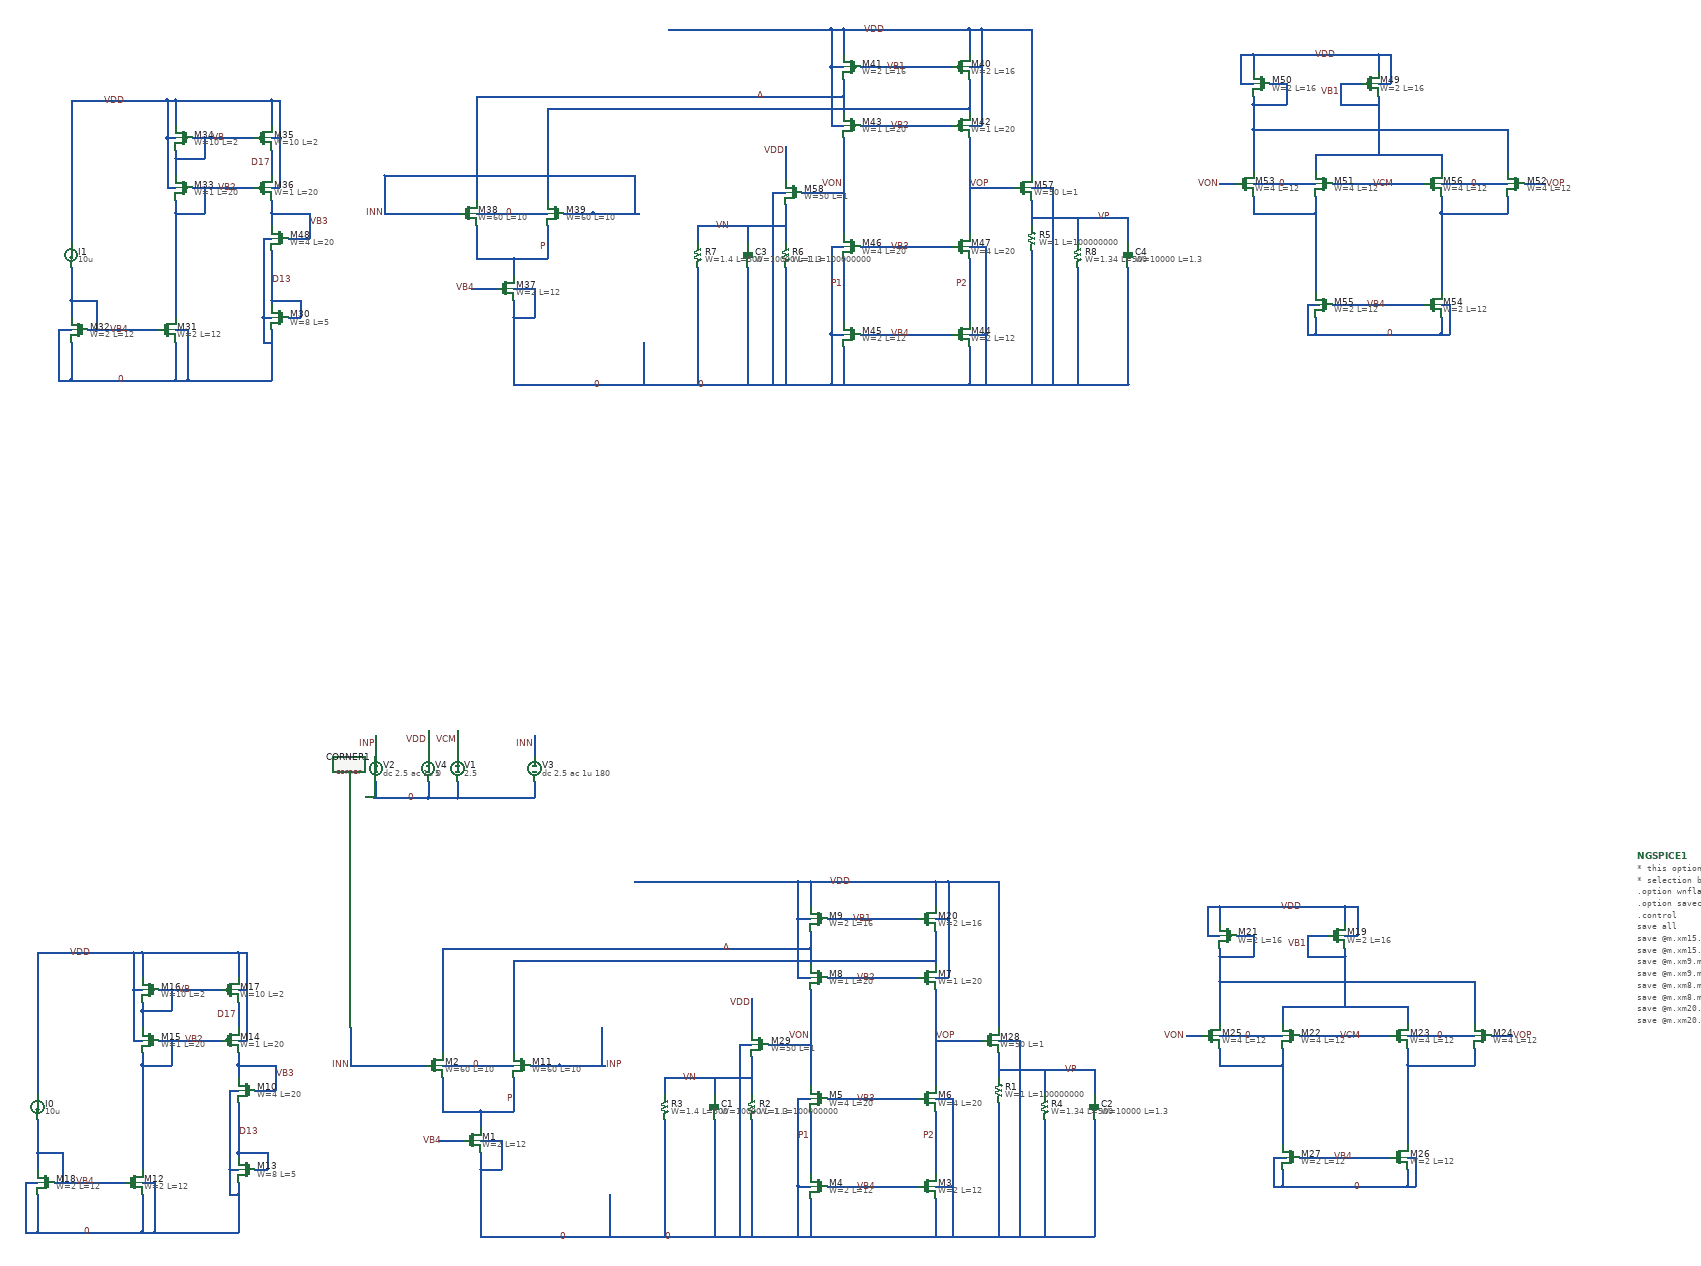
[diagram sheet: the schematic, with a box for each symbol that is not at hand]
v {xschem version=3.4.5 file_version=1.2
}
G {}
K {}
V {}
S {}
E {}
B 2 -210 300 1560 1150 {flags=graph
y1=-17.303233

ypos1=0
ypos2=2


unity=1


divx=5
subdivx=8
xlabmag=1.0
ylabmag=1.0


dataset=-1
unitx=1
logx=1
logy=0
color=4
node="\\"vp db20()\\""
x1=2.4468025
hilight_wave=-1

y2=-15.322405

divy=10
subdivy=4
x2=6.935988}
B 2 -1120 400 -320 800 {flags=graph
y1=26.38169

ypos1=0
ypos2=2
divy=5
subdivy=1
unity=1
x1=2.4468025

divx=5
subdivx=1
xlabmag=1.0
ylabmag=1.0
node=ph(vp)
color=4
dataset=-1
unitx=1
logx=0
logy=0

y2=80.30864
x2=6.935988}
N -130 -610 -130 -550 {
lab=VDD}
N 170 -610 170 -550 {
lab=VDD}
N 170 -420 170 -410 {
lab=#net1}
N -130 -450 -130 -410 {
lab=A}
N -130 -350 -130 -120 {
lab=VON}
N -130 -60 -130 90 {
lab=P1}
N -130 150 -130 240 {
lab=0}
N -130 240 170 240 {
lab=0}
N 170 150 170 240 {
lab=0}
N 170 -60 170 90 {
lab=P2}
N 170 -350 170 -120 {
lab=VOP}
N -90 -90 130 -90 {
lab=VB3}
N -90 120 130 120 {
lab=VB4}
N -160 120 -130 120 {
lab=0}
N -160 120 -160 240 {
lab=0}
N -160 240 -130 240 {
lab=0}
N 170 120 210 120 {
lab=0}
N 210 120 210 240 {
lab=0}
N 170 240 210 240 {
lab=0}
N -160 -90 -130 -90 {
lab=0}
N -160 -90 -160 120 {
lab=0}
N 170 -90 210 -90 {
lab=0}
N 210 -90 210 120 {
lab=0}
N -1010 -170 -840 -170 {
lab=0}
N -1100 -170 -1050 -170 {
lab=INN}
N -800 -170 -760 -170 {
lab=INP}
N -1010 -140 -1010 -60 {
lab=P}
N -920 -60 -840 -60 {
lab=P}
N -840 -140 -840 -60 {
lab=P}
N -920 -60 -920 -20 {
lab=P}
N -1020 10 -960 10 {
lab=VB4}
N -920 80 -920 240 {
lab=0}
N -540 240 -160 240 {
lab=0}
N -90 -380 130 -380 {
lab=VB2}
N -90 -520 130 -520 {
lab=VB1}
N 170 -520 200 -520 {
lab=VDD}
N 200 -610 200 -520 {
lab=VDD}
N 170 -610 200 -610 {
lab=VDD}
N -160 -520 -130 -520 {
lab=VDD}
N -160 -610 -160 -520 {
lab=VDD}
N -130 -610 170 -610 {
lab=VDD}
N 170 -380 200 -380 {
lab=VDD}
N 200 -520 200 -380 {
lab=VDD}
N -160 -380 -130 -380 {
lab=VDD}
N -160 -520 -160 -380 {
lab=VDD}
N -1010 -450 -1010 -200 {
lab=A}
N -630 -450 -130 -450 {
lab=A}
N -840 -420 -840 -200 {
lab=#net1}
N -460 -420 170 -420 {
lab=#net1}
N -1980 40 -1980 80 {
lab=VB4}
N -1980 140 -1980 230 {
lab=0}
N -1730 140 -1730 230 {
lab=0}
N -1730 110 -1700 110 {
lab=0}
N -1700 110 -1700 230 {
lab=0}
N -1730 230 -1700 230 {
lab=0}
N -2010 110 -1980 110 {
lab=0}
N -2010 110 -2010 230 {
lab=0}
N -2010 230 -1980 230 {
lab=0}
N -1920 110 -1770 110 {
lab=VB4}
N -1980 40 -1920 40 {
lab=VB4}
N -1920 40 -1920 110 {
lab=VB4}
N -1730 -440 -1730 -380 {
lab=VDD}
N -1730 -440 -1500 -440 {
lab=VDD}
N -1500 -440 -1500 -380 {
lab=VDD}
N -1660 -350 -1540 -350 {
lab=VB}
N -1660 -350 -1660 -300 {
lab=VB}
N -1730 -300 -1660 -300 {
lab=VB}
N -1730 -300 -1730 -260 {
lab=VB}
N -1980 -440 -1980 -100 {
lab=VDD}
N -1750 -440 -1730 -440 {
lab=VDD}
N -1730 -170 -1730 80 {
lab=VB2}
N -1660 -230 -1540 -230 {
lab=VB2}
N -1660 -230 -1660 -170 {
lab=VB2}
N -1730 -170 -1660 -170 {
lab=VB2}
N -1500 -320 -1500 -260 {
lab=D17}
N -1500 -230 -1480 -230 {
lab=VDD}
N -1480 -350 -1480 -230 {
lab=VDD}
N -1500 -440 -1480 -440 {
lab=VDD}
N -1500 -350 -1480 -350 {
lab=VDD}
N -1750 -230 -1730 -230 {
lab=VDD}
N -1750 -350 -1750 -230 {
lab=VDD}
N -1750 -350 -1730 -350 {
lab=VDD}
N -1500 -170 -1500 -140 {
lab=VB3}
N -1500 40 -1500 50 {
lab=D13}
N -1460 -110 -1410 -110 {
lab=VB3}
N -1410 -170 -1410 -110 {
lab=VB3}
N -1500 -170 -1410 -170 {
lab=VB3}
N -1500 140 -1500 230 {
lab=0}
N -1700 230 -1500 230 {
lab=0}
N -1520 80 -1500 80 {
lab=0}
N -1520 80 -1520 140 {
lab=0}
N -1520 140 -1500 140 {
lab=0}
N -1460 80 -1430 80 {
lab=D13}
N -1430 40 -1430 80 {
lab=D13}
N -1500 40 -1430 40 {
lab=D13}
N -1045 -970 -1045 -910 {
lab=VDD}
N -1175 -810 -1045 -810 {
lab=0}
N -1045 -850 -1045 -810 {
lab=0}
N -920 10 -870 10 {
lab=0}
N -870 10 -870 80 {
lab=0}
N -920 80 -870 80 {
lab=0}
N -1520 -110 -1520 80 {
lab=0}
N -1520 -110 -1500 -110 {
lab=0}
N 1150 -480 1180 -480 {
lab=VDD}
N 820 -480 850 -480 {
lab=VDD}
N 1040 -240 1260 -240 {
lab=VCM}
N 1300 -240 1460 -240 {
lab=0}
N 980 50 1010 50 {
lab=0}
N 1300 50 1320 50 {
lab=0}
N 1000 -310 1000 -270 {
lab=VB1}
N 1150 -310 1300 -310 {
lab=VB1}
N 1300 -310 1300 -270 {
lab=VB1}
N 850 -370 850 -270 {
lab=#net2}
N 850 -370 1460 -370 {
lab=#net2}
N 1460 -370 1460 -270 {
lab=#net2}
N 850 -430 850 -370 {
lab=#net2}
N 1150 -430 1150 -310 {
lab=VB1}
N 850 -210 850 -170 {
lab=#net3}
N 850 -170 1000 -170 {
lab=#net3}
N 1000 -210 1000 -170 {
lab=#net3}
N 1300 -210 1300 -170 {
lab=#net4}
N 1300 -170 1460 -170 {
lab=#net4}
N 1460 -210 1460 -170 {
lab=#net4}
N 1000 -170 1000 20 {
lab=#net3}
N 1300 -170 1300 20 {
lab=#net4}
N 1040 50 1270 50 {
lab=VB4}
N 1000 80 1000 120 {
lab=0}
N 1000 120 1300 120 {
lab=0}
N 1300 80 1300 120 {
lab=0}
N 930 -480 930 -430 {
lab=#net2}
N 850 -430 930 -430 {
lab=#net2}
N 1060 -480 1060 -430 {
lab=VB1}
N 1060 -430 1150 -430 {
lab=VB1}
N 890 -480 930 -480 {
lab=#net2}
N 1060 -480 1110 -480 {
lab=VB1}
N 850 -550 850 -510 {
lab=VDD}
N 1150 -550 1150 -510 {
lab=VDD}
N 770 -240 810 -240 {
lab=VON}
N 1500 -240 1550 -240 {
lab=VOP}
N 820 -550 820 -480 {
lab=VDD}
N 850 -550 1150 -550 {
lab=VDD}
N 1180 -550 1180 -480 {
lab=VDD}
N 1150 -550 1180 -550 {
lab=VDD}
N 980 50 980 120 {
lab=0}
N 980 120 1000 120 {
lab=0}
N 1320 50 1320 120 {
lab=0}
N 1300 120 1320 120 {
lab=0}
N -975 -970 -975 -910 {
lab=VCM}
N -975 -850 -975 -810 {
lab=0}
N -975 -810 -790 -810 {
lab=0}
N -790 -960 -790 -910 {
lab=INN}
N -790 -850 -790 -810 {
lab=0}
N -160 -610 -130 -610 {
lab=VDD}
N -1010 -60 -920 -60 {
lab=P}
N -130 -490 -130 -450 {
lab=A}
N 170 -490 170 -420 {
lab=#net1}
N -1980 -40 -1980 40 {
lab=VB4}
N -1940 110 -1920 110 {
lab=VB4}
N -1690 -350 -1660 -350 {
lab=VB}
N -1730 -320 -1730 -300 {
lab=VB}
N -1690 -230 -1660 -230 {
lab=VB2}
N -1730 -200 -1730 -170 {
lab=VB2}
N -1480 -440 -1480 -350 {
lab=VDD}
N -1980 -440 -1750 -440 {
lab=VDD}
N -1750 -440 -1750 -350 {
lab=VDD}
N -1500 -200 -1500 -170 {
lab=VB3}
N -1500 110 -1500 140 {
lab=0}
N -1500 -80 -1500 40 {
lab=D13}
N -920 40 -920 80 {
lab=0}
N 850 -240 1000 -240 {
lab=0}
N 1000 -310 1150 -310 {
lab=VB1}
N 850 -450 850 -430 {
lab=#net2}
N 1150 -450 1150 -430 {
lab=VB1}
N 820 -550 850 -550 {
lab=VDD}
N -1045 -810 -975 -810 {
lab=0}
N -1980 230 -1730 230 {
lab=0}
N 170 -230 280 -230 {
lab=VOP}
N 200 -610 310 -610 {
lab=VDD}
N 320 -230 350 -230 {
lab=0}
N 350 -230 370 -230 {
lab=0}
N 320 -610 320 -260 {
lab=VDD}
N 280 -610 320 -610 {
lab=VDD}
N 320 -200 320 -140 {
lab=VP}
N 320 -80 320 240 {
lab=0}
N 210 240 320 240 {
lab=0}
N -270 -330 -270 -250 {
lab=VDD}
N -230 -220 -130 -220 {
lab=VON}
N -270 -190 -270 -100 {
lab=VN}
N -270 -40 -270 240 {
lab=0}
N -300 -220 -270 -220 {
lab=0}
N -300 -220 -300 230 {
lab=0}
N -300 230 -300 240 {
lab=0}
N 370 -230 370 230 {
lab=0}
N 370 230 370 240 {
lab=0}
N 320 240 370 240 {
lab=0}
N -1010 -450 -910 -450 {
lab=A}
N -560 -420 -460 -420 {
lab=#net1}
N -920 240 -820 240 {
lab=0}
N -420 -140 -270 -140 {
lab=VN}
N -480 -140 -480 -100 {
lab=VN}
N -360 -140 -360 -100 {
lab=VN}
N -480 -40 -480 240 {
lab=0}
N -360 -40 -360 240 {
lab=0}
N -480 -140 -420 -140 {
lab=VN}
N 430 -140 430 -100 {
lab=VP}
N 550 -140 550 -100 {
lab=VP}
N 430 -40 430 240 {
lab=0}
N 550 -40 550 240 {
lab=0}
N 320 -160 550 -160 {
lab=VP}
N 550 -160 550 -140 {
lab=VP}
N 430 -160 430 -140 {
lab=VP}
N 380 240 550 240 {
lab=0}
N 330 240 550 240 {
lab=0}
N -550 -610 -160 -610 {
lab=VDD}
N -1120 -170 -1080 -170 {
lab=INN}
N -1230 -170 -1180 -170 {
lab=INN}
N -830 240 -520 240 {
lab=0}
N -920 -450 -590 -450 {
lab=A}
N -840 -420 -550 -420 {
lab=#net1}
N -770 -170 -730 -170 {
lab=INP}
N -790 240 -410 240 {
lab=0}
N -770 -170 -730 -170 {
lab=INP}
N -670 -170 -620 -170 {
lab=INP}
N -610 140 -610 240 {
lab=0}
N -730 -170 -660 -170 {
lab=INP}
N -1180 -170 -1100 -170 {
lab=INN}
N -1230 -260 -1230 -170 {
lab=INN}
N -630 -260 -630 -170 {
lab=INP}
N -1170 -960 -1170 -910 {
lab=INP}
N -1170 -850 -1170 -810 {
lab=0}
N -50 -2650 -50 -2590 {
lab=VDD}
N 250 -2650 250 -2590 {
lab=VDD}
N 250 -2460 250 -2450 {
lab=#net1}
N -50 -2490 -50 -2450 {
lab=A}
N -50 -2390 -50 -2160 {
lab=VON}
N -50 -2100 -50 -1950 {
lab=P1}
N -50 -1890 -50 -1800 {
lab=0}
N -50 -1800 250 -1800 {
lab=0}
N 250 -1890 250 -1800 {
lab=0}
N 250 -2100 250 -1950 {
lab=P2}
N 250 -2390 250 -2160 {
lab=VOP}
N -10 -2130 210 -2130 {
lab=VB3}
N -10 -1920 210 -1920 {
lab=VB4}
N -80 -1920 -50 -1920 {
lab=0}
N -80 -1920 -80 -1800 {
lab=0}
N -80 -1800 -50 -1800 {
lab=0}
N 250 -1920 290 -1920 {
lab=0}
N 290 -1920 290 -1800 {
lab=0}
N 250 -1800 290 -1800 {
lab=0}
N -80 -2130 -50 -2130 {
lab=0}
N -80 -2130 -80 -1920 {
lab=0}
N 250 -2130 290 -2130 {
lab=0}
N 290 -2130 290 -1920 {
lab=0}
N -930 -2210 -760 -2210 {
lab=0}
N -1020 -2210 -970 -2210 {
lab=INN}
N -720 -2210 -680 -2210 {
lab=INP}
N -930 -2180 -930 -2100 {
lab=P}
N -840 -2100 -760 -2100 {
lab=P}
N -760 -2180 -760 -2100 {
lab=P}
N -840 -2100 -840 -2060 {
lab=P}
N -940 -2030 -880 -2030 {
lab=VB4}
N -840 -1960 -840 -1800 {
lab=0}
N -460 -1800 -80 -1800 {
lab=0}
N -10 -2420 210 -2420 {
lab=VB2}
N -10 -2560 210 -2560 {
lab=VB1}
N 250 -2560 280 -2560 {
lab=VDD}
N 280 -2650 280 -2560 {
lab=VDD}
N 250 -2650 280 -2650 {
lab=VDD}
N -80 -2560 -50 -2560 {
lab=VDD}
N -80 -2650 -80 -2560 {
lab=VDD}
N -50 -2650 250 -2650 {
lab=VDD}
N 250 -2420 280 -2420 {
lab=VDD}
N 280 -2560 280 -2420 {
lab=VDD}
N -80 -2420 -50 -2420 {
lab=VDD}
N -80 -2560 -80 -2420 {
lab=VDD}
N -930 -2490 -930 -2240 {
lab=A}
N -550 -2490 -50 -2490 {
lab=A}
N -760 -2460 -760 -2240 {
lab=#net1}
N -380 -2460 250 -2460 {
lab=#net1}
N -1900 -2000 -1900 -1960 {
lab=VB4}
N -1900 -1900 -1900 -1810 {
lab=0}
N -1650 -1900 -1650 -1810 {
lab=0}
N -1650 -1930 -1620 -1930 {
lab=0}
N -1620 -1930 -1620 -1810 {
lab=0}
N -1650 -1810 -1620 -1810 {
lab=0}
N -1930 -1930 -1900 -1930 {
lab=0}
N -1930 -1930 -1930 -1810 {
lab=0}
N -1930 -1810 -1900 -1810 {
lab=0}
N -1840 -1930 -1690 -1930 {
lab=VB4}
N -1900 -2000 -1840 -2000 {
lab=VB4}
N -1840 -2000 -1840 -1930 {
lab=VB4}
N -1650 -2480 -1650 -2420 {
lab=VDD}
N -1650 -2480 -1420 -2480 {
lab=VDD}
N -1420 -2480 -1420 -2420 {
lab=VDD}
N -1580 -2390 -1460 -2390 {
lab=VB}
N -1580 -2390 -1580 -2340 {
lab=VB}
N -1650 -2340 -1580 -2340 {
lab=VB}
N -1650 -2340 -1650 -2300 {
lab=VB}
N -1900 -2480 -1900 -2140 {
lab=VDD}
N -1670 -2480 -1650 -2480 {
lab=VDD}
N -1650 -2210 -1650 -1960 {
lab=VB2}
N -1580 -2270 -1460 -2270 {
lab=VB2}
N -1580 -2270 -1580 -2210 {
lab=VB2}
N -1650 -2210 -1580 -2210 {
lab=VB2}
N -1420 -2360 -1420 -2300 {
lab=D17}
N -1420 -2270 -1400 -2270 {
lab=VDD}
N -1400 -2390 -1400 -2270 {
lab=VDD}
N -1420 -2480 -1400 -2480 {
lab=VDD}
N -1420 -2390 -1400 -2390 {
lab=VDD}
N -1670 -2270 -1650 -2270 {
lab=VDD}
N -1670 -2390 -1670 -2270 {
lab=VDD}
N -1670 -2390 -1650 -2390 {
lab=VDD}
N -1420 -2210 -1420 -2180 {
lab=VB3}
N -1420 -2000 -1420 -1990 {
lab=D13}
N -1380 -2150 -1330 -2150 {
lab=VB3}
N -1330 -2210 -1330 -2150 {
lab=VB3}
N -1420 -2210 -1330 -2210 {
lab=VB3}
N -1420 -1900 -1420 -1810 {
lab=0}
N -1620 -1810 -1420 -1810 {
lab=0}
N -1440 -1960 -1420 -1960 {
lab=0}
N -1440 -1960 -1440 -1900 {
lab=0}
N -1440 -1900 -1420 -1900 {
lab=0}
N -1380 -1960 -1350 -1960 {
lab=D13}
N -1350 -2000 -1350 -1960 {
lab=D13}
N -1420 -2000 -1350 -2000 {
lab=D13}
N -840 -2030 -790 -2030 {
lab=0}
N -790 -2030 -790 -1960 {
lab=0}
N -840 -1960 -790 -1960 {
lab=0}
N -1440 -2150 -1440 -1960 {
lab=0}
N -1440 -2150 -1420 -2150 {
lab=0}
N 1230 -2520 1260 -2520 {
lab=VDD}
N 900 -2520 930 -2520 {
lab=VDD}
N 1120 -2280 1340 -2280 {
lab=VCM}
N 1380 -2280 1540 -2280 {
lab=0}
N 1060 -1990 1090 -1990 {
lab=0}
N 1380 -1990 1400 -1990 {
lab=0}
N 1080 -2350 1080 -2310 {
lab=VB1}
N 1230 -2350 1380 -2350 {
lab=VB1}
N 1380 -2350 1380 -2310 {
lab=VB1}
N 930 -2410 930 -2310 {
lab=#net2}
N 930 -2410 1540 -2410 {
lab=#net2}
N 1540 -2410 1540 -2310 {
lab=#net2}
N 930 -2470 930 -2410 {
lab=#net2}
N 1230 -2470 1230 -2350 {
lab=VB1}
N 930 -2250 930 -2210 {
lab=#net3}
N 930 -2210 1080 -2210 {
lab=#net3}
N 1080 -2250 1080 -2210 {
lab=#net3}
N 1380 -2250 1380 -2210 {
lab=#net4}
N 1380 -2210 1540 -2210 {
lab=#net4}
N 1540 -2250 1540 -2210 {
lab=#net4}
N 1080 -2210 1080 -2020 {
lab=#net3}
N 1380 -2210 1380 -2020 {
lab=#net4}
N 1120 -1990 1350 -1990 {
lab=VB4}
N 1080 -1960 1080 -1920 {
lab=0}
N 1080 -1920 1380 -1920 {
lab=0}
N 1380 -1960 1380 -1920 {
lab=0}
N 1010 -2520 1010 -2470 {
lab=#net2}
N 930 -2470 1010 -2470 {
lab=#net2}
N 1140 -2520 1140 -2470 {
lab=VB1}
N 1140 -2470 1230 -2470 {
lab=VB1}
N 970 -2520 1010 -2520 {
lab=#net2}
N 1140 -2520 1190 -2520 {
lab=VB1}
N 930 -2590 930 -2550 {
lab=VDD}
N 1230 -2590 1230 -2550 {
lab=VDD}
N 850 -2280 890 -2280 {
lab=VON}
N 1580 -2280 1630 -2280 {
lab=VOP}
N 900 -2590 900 -2520 {
lab=VDD}
N 930 -2590 1230 -2590 {
lab=VDD}
N 1260 -2590 1260 -2520 {
lab=VDD}
N 1230 -2590 1260 -2590 {
lab=VDD}
N 1060 -1990 1060 -1920 {
lab=0}
N 1060 -1920 1080 -1920 {
lab=0}
N 1400 -1990 1400 -1920 {
lab=0}
N 1380 -1920 1400 -1920 {
lab=0}
N -80 -2650 -50 -2650 {
lab=VDD}
N -930 -2100 -840 -2100 {
lab=P}
N -50 -2530 -50 -2490 {
lab=A}
N 250 -2530 250 -2460 {
lab=#net1}
N -1900 -2080 -1900 -2000 {
lab=VB4}
N -1860 -1930 -1840 -1930 {
lab=VB4}
N -1610 -2390 -1580 -2390 {
lab=VB}
N -1650 -2360 -1650 -2340 {
lab=VB}
N -1610 -2270 -1580 -2270 {
lab=VB2}
N -1650 -2240 -1650 -2210 {
lab=VB2}
N -1400 -2480 -1400 -2390 {
lab=VDD}
N -1900 -2480 -1670 -2480 {
lab=VDD}
N -1670 -2480 -1670 -2390 {
lab=VDD}
N -1420 -2240 -1420 -2210 {
lab=VB3}
N -1420 -1930 -1420 -1900 {
lab=0}
N -1420 -2120 -1420 -2000 {
lab=D13}
N -840 -2000 -840 -1960 {
lab=0}
N 930 -2280 1080 -2280 {
lab=0}
N 1080 -2350 1230 -2350 {
lab=VB1}
N 930 -2490 930 -2470 {
lab=#net2}
N 1230 -2490 1230 -2470 {
lab=VB1}
N 900 -2590 930 -2590 {
lab=VDD}
N -1900 -1810 -1650 -1810 {
lab=0}
N 250 -2270 360 -2270 {
lab=VOP}
N 280 -2650 390 -2650 {
lab=VDD}
N 400 -2270 430 -2270 {
lab=0}
N 430 -2270 450 -2270 {
lab=0}
N 400 -2650 400 -2300 {
lab=VDD}
N 360 -2650 400 -2650 {
lab=VDD}
N 400 -2240 400 -2180 {
lab=VP}
N 400 -2120 400 -1800 {
lab=0}
N 290 -1800 400 -1800 {
lab=0}
N -190 -2370 -190 -2290 {
lab=VDD}
N -150 -2260 -50 -2260 {
lab=VON}
N -190 -2230 -190 -2140 {
lab=VN}
N -190 -2080 -190 -1800 {
lab=0}
N -220 -2260 -190 -2260 {
lab=0}
N -220 -2260 -220 -1810 {
lab=0}
N -220 -1810 -220 -1800 {
lab=0}
N 450 -2270 450 -1810 {
lab=0}
N 450 -1810 450 -1800 {
lab=0}
N 400 -1800 450 -1800 {
lab=0}
N -930 -2490 -830 -2490 {
lab=A}
N -480 -2460 -380 -2460 {
lab=#net1}
N -840 -1800 -740 -1800 {
lab=0}
N -340 -2180 -190 -2180 {
lab=VN}
N -400 -2180 -400 -2140 {
lab=VN}
N -280 -2180 -280 -2140 {
lab=VN}
N -400 -2080 -400 -1800 {
lab=0}
N -280 -2080 -280 -1800 {
lab=0}
N -400 -2180 -340 -2180 {
lab=VN}
N 510 -2180 510 -2140 {
lab=VP}
N 630 -2180 630 -2140 {
lab=VP}
N 510 -2080 510 -1800 {
lab=0}
N 630 -2080 630 -1800 {
lab=0}
N 400 -2200 630 -2200 {
lab=VP}
N 630 -2200 630 -2180 {
lab=VP}
N 510 -2200 510 -2180 {
lab=VP}
N 460 -1800 630 -1800 {
lab=0}
N 410 -1800 630 -1800 {
lab=0}
N -470 -2650 -80 -2650 {
lab=VDD}
N -1040 -2210 -1000 -2210 {
lab=INN}
N -1150 -2210 -1100 -2210 {
lab=INN}
N -750 -1800 -440 -1800 {
lab=0}
N -840 -2490 -510 -2490 {
lab=A}
N -760 -2460 -470 -2460 {
lab=#net1}
N -690 -2210 -650 -2210 {
lab=INP}
N -710 -1800 -330 -1800 {
lab=0}
N -690 -2210 -650 -2210 {
lab=INP}
N -590 -2210 -540 -2210 {
lab=INP}
N -530 -1900 -530 -1800 {
lab=0}
N -650 -2210 -580 -2210 {
lab=INP}
N -1100 -2210 -1020 -2210 {
lab=INN}
N -1150 -2300 -1150 -2210 {
lab=INN}
N -550 -2300 -550 -2210 {
lab=INP}
N -1150 -2300 -1140 -2300 {}
N -1150 -2300 -550 -2300 {}
C {devices/isource.sym} -1980 -70 0 0 {name=I0 value=10u
}
C {devices/lab_pin.sym} -1840 110 0 0 {name=p1 sig_type=std_logic lab=VB4
}
C {devices/lab_pin.sym} -1010 10 0 0 {name=p2 sig_type=std_logic lab=VB4}
C {devices/lab_pin.sym} 30 120 0 0 {name=p3 sig_type=std_logic lab=VB4}
C {devices/lab_pin.sym} -920 -170 0 0 {name=p4 sig_type=std_logic lab=0}
C {devices/lab_pin.sym} -460 240 1 0 {name=p7 sig_type=std_logic lab=0}
C {devices/lab_pin.sym} -1850 230 1 0 {name=p8 sig_type=std_logic lab=0}
C {devices/lab_pin.sym} -1850 -440 1 0 {name=p9 sig_type=std_logic lab=VDD}
C {devices/lab_pin.sym} -30 -610 1 0 {name=p10 sig_type=std_logic lab=VDD}
C {devices/lab_pin.sym} 20 -520 1 0 {name=p13 sig_type=std_logic lab=VB1}
C {devices/lab_pin.sym} -1580 -230 1 0 {name=p14 sig_type=std_logic lab=VB2}
C {devices/lab_pin.sym} 30 -380 3 0 {name=p15 sig_type=std_logic lab=VB2}
C {devices/lab_pin.sym} -1410 -150 2 0 {name=p16 sig_type=std_logic lab=VB3}
C {devices/lab_pin.sym} 30 -90 1 0 {name=p17 sig_type=std_logic lab=VB3}
C {devices/code_shown.sym} 1850 -670 0 0 {name=NGSPICE1
only_toplevel=true
value="* this option enables mos model bin 
* selection based on W/NF instead of W
.option wnflag=1 
.option savecurrents

.control
save all
save @m.xm15.msky130_fd_pr__pfet_g5v0d10v5[vth]
save @m.xm15.msky130_fd_pr__pfet_g5v0d10v5[gm]
save @m.xm9.msky130_fd_pr__pfet_g5v0d10v5[vth]
save @m.xm9.msky130_fd_pr__pfet_g5v0d10v5[gm]
save @m.xm8.msky130_fd_pr__pfet_g5v0d10v5[vth]
save @m.xm8.msky130_fd_pr__pfet_g5v0d10v5[gm]
save @m.xm20.msky130_fd_pr__pfet_g5v0d10v5[vth]
save @m.xm20.msky130_fd_pr__pfet_g5v0d10v5[gm]
save @m.xm7.msky130_fd_pr__pfet_g5v0d10v5[vth]
save @m.xm7.msky130_fd_pr__pfet_g5v0d10v5[gm]
save @m.xm10.msky130_fd_pr__nfet_g5v0d10v5[gm]
save @m.xm10.msky130_fd_pr__nfet_g5v0d10v5[vth]
save @m.xm14.msky130_fd_pr__pfet_g5v0d10v5[gm]
save @m.xm14.msky130_fd_pr__pfet_g5v0d10v5[vth]
save @m.xm16.msky130_fd_pr__pfet_g5v0d10v5[gm]
save @m.xm16.msky130_fd_pr__pfet_g5v0d10v5[vth]
save @m.xm17.msky130_fd_pr__pfet_g5v0d10v5[gm]
save @m.xm17.msky130_fd_pr__pfet_g5v0d10v5[vth]
save @m.xm13.msky130_fd_pr__nfet_g5v0d10v5[gm]
save @m.xm13.msky130_fd_pr__nfet_g5v0d10v5[vth]
save @m.xm12.msky130_fd_pr__nfet_g5v0d10v5[vth]
save @m.xm18.msky130_fd_pr__nfet_g5v0d10v5[vth]
*folded 
save @m.xm2.msky130_fd_pr__nfet_g5v0d10v5[vth]
save @m.xm11.msky130_fd_pr__nfet_g5v0d10v5[vth]
save @m.xm1.msky130_fd_pr__nfet_g5v0d10v5[vth]
save @m.xm5.msky130_fd_pr__nfet_g5v0d10v5[vth]
save @m.xm6.msky130_fd_pr__nfet_g5v0d10v5[vth]
save @m.xm4.msky130_fd_pr__nfet_g5v0d10v5[vth]
save @m.xm3.msky130_fd_pr__nfet_g5v0d10v5[vth]
save @m.xm7.msky130_fd_pr__pfet_g5v0d10v5[vth]
save @m.xm8.msky130_fd_pr__pfet_g5v0d10v5[vth]
save @m.xm9.msky130_fd_pr__pfet_g5v0d10v5[vth]
save @m.xm20.msky130_fd_pr__pfet_g5v0d10v5[vth]
*CMFB
save @m.xm21.msky130_fd_pr__pfet_g5v0d10v5[vth]
save @m.xm19.msky130_fd_pr__pfet_g5v0d10v5[vth]
save @m.xm22.msky130_fd_pr__nfet_g5v0d10v5[vth]
save @m.xm23.msky130_fd_pr__nfet_g5v0d10v5[vth]
save @m.xm25.msky130_fd_pr__nfet_g5v0d10v5[vth]
save @m.xm27.msky130_fd_pr__nfet_g5v0d10v5[vth]
save @m.xm26.msky130_fd_pr__nfet_g5v0d10v5[vth]
save @m.xm24.msky130_fd_pr__nfet_g5v0d10v5[vth]
save current 


write CMRR_Folded.raw

op
print VON VOP VB2 VB
*print @m.xm18.msky130_fd_pr__nfet_g5v0d10v5
*print @m.xm12.msky130_fd_pr__nfet_g5v0d10v5
*print @m.xm13.msky130_fd_pr__nfet_g5v0d10v5
*print @m.xm10.msky130_fd_pr__nfet_g5v0d10v5
*print @m.xm14.msky130_fd_pr__pfet_g5v0d10v5
*print @m.xm17.msky130_fd_pr__pfet_g5v0d10v5
*print @m.xm15.msky130_fd_pr__pfet_g5v0d10v5
*print @m.xm16.msky130_fd_pr__pfet_g5v0d10v5
*Folded cascode 
*print @m.xm9.msky130_fd_pr__pfet_g5v0d10v5
*print @m.xm8.msky130_fd_pr__pfet_g5v0d10v5
*print @m.xm5.msky130_fd_pr__nfet_g5v0d10v5
*print @m.xm4.msky130_fd_pr__nfet_g5v0d10v5
*print @m.xm1.msky130_fd_pr__nfet_g5v0d10v5
*print @m.xm2.msky130_fd_pr__nfet_g5v0d10v5
*print @m.xm11.msky130_fd_pr__nfet_g5v0d10v5
*CMFB
*print @m.xm23.msky130_fd_pr__nfet_g5v0d10v5
*print @m.xm24.msky130_fd_pr__nfet_g5v0d10v5
*print @m.xm25.msky130_fd_pr__nfet_g5v0d10v5
*print @m.xm22.msky130_fd_pr__nfet_g5v0d10v5
print @m.xm9.msky130_fd_pr__pfet_g5v0d10v5
print @m.xm8.msky130_fd_pr__pfet_g5v0d10v5
print @m.xm4.msky130_fd_pr__nfet_g5v0d10v5
print @m.xm5.msky130_fd_pr__nfet_g5v0d10v5
write CMRR_Folded.raw
ac dec 10 1 1e9
  remzerovec
  write CMRR_Folded.raw
quit 0
.endc
" }
C {sky130_fd_pr/corner.sym} -1555 -855 0 0 {name=CORNER1 only_toplevel=true corner=tt}
C {devices/vsource.sym} -1045 -880 0 0 {name=V4 value=5 savecurrent=false}
C {devices/lab_pin.sym} -1045 -950 0 0 {name=p22 sig_type=std_logic lab=VDD}
C {devices/lab_pin.sym} -1075 -810 1 0 {name=p26 sig_type=std_logic lab=0}
C {sky130_fd_pr/nfet_g5v0d10v5.sym} -1480 80 0 1 {name=M13
L=5
W=8
nf=1
mult=2
ad="'int((nf+1)/2) * W/nf * 0.29'" 
pd="'2*int((nf+1)/2) * (W/nf + 0.29)'"
as="'int((nf+2)/2) * W/nf * 0.29'" 
ps="'2*int((nf+2)/2) * (W/nf + 0.29)'"
nrd="'0.29 / W'" nrs="'0.29 / W'"
sa=0 sb=0 sd=0
model=nfet_g5v0d10v5
spiceprefix=X
}
C {sky130_fd_pr/nfet_g5v0d10v5.sym} -1750 110 0 0 {name=M12
L=12
W=2
nf=1
mult=2
ad="'int((nf+1)/2) * W/nf * 0.29'" 
pd="'2*int((nf+1)/2) * (W/nf + 0.29)'"
as="'int((nf+2)/2) * W/nf * 0.29'" 
ps="'2*int((nf+2)/2) * (W/nf + 0.29)'"
nrd="'0.29 / W'" nrs="'0.29 / W'"
sa=0 sb=0 sd=0
model=nfet_g5v0d10v5
spiceprefix=X
}
C {sky130_fd_pr/nfet_g5v0d10v5.sym} -1960 110 0 1 {name=M18
L=12
W=2
nf=1
mult=2
ad="'int((nf+1)/2) * W/nf * 0.29'" 
pd="'2*int((nf+1)/2) * (W/nf + 0.29)'"
as="'int((nf+2)/2) * W/nf * 0.29'" 
ps="'2*int((nf+2)/2) * (W/nf + 0.29)'"
nrd="'0.29 / W'" nrs="'0.29 / W'"
sa=0 sb=0 sd=0
model=nfet_g5v0d10v5
spiceprefix=X
}
C {sky130_fd_pr/pfet_g5v0d10v5.sym} -1710 -230 0 1 {name=M15
L=20
W=1
nf=1
mult=32
ad="'int((nf+1)/2) * W/nf * 0.29'" 
pd="'2*int((nf+1)/2) * (W/nf + 0.29)'"
as="'int((nf+2)/2) * W/nf * 0.29'" 
ps="'2*int((nf+2)/2) * (W/nf + 0.29)'"
nrd="'0.29 / W'" nrs="'0.29 / W'"
sa=0 sb=0 sd=0
model=pfet_g5v0d10v5
spiceprefix=X
}
C {sky130_fd_pr/pfet_g5v0d10v5.sym} -1710 -350 0 1 {name=M16
L=2
W=10
nf=1
mult=2
ad="'int((nf+1)/2) * W/nf * 0.29'" 
pd="'2*int((nf+1)/2) * (W/nf + 0.29)'"
as="'int((nf+2)/2) * W/nf * 0.29'" 
ps="'2*int((nf+2)/2) * (W/nf + 0.29)'"
nrd="'0.29 / W'" nrs="'0.29 / W'"
sa=0 sb=0 sd=0
model=pfet_g5v0d10v5
spiceprefix=X
}
C {sky130_fd_pr/pfet_g5v0d10v5.sym} -1520 -350 0 0 {name=M17
L=2
W=10
nf=1
mult=2
ad="'int((nf+1)/2) * W/nf * 0.29'" 
pd="'2*int((nf+1)/2) * (W/nf + 0.29)'"
as="'int((nf+2)/2) * W/nf * 0.29'" 
ps="'2*int((nf+2)/2) * (W/nf + 0.29)'"
nrd="'0.29 / W'" nrs="'0.29 / W'"
sa=0 sb=0 sd=0
model=pfet_g5v0d10v5
spiceprefix=X
}
C {sky130_fd_pr/pfet_g5v0d10v5.sym} -1520 -230 0 0 {name=M14
L=20
W=1
nf=1
mult=32
ad="'int((nf+1)/2) * W/nf * 0.29'" 
pd="'2*int((nf+1)/2) * (W/nf + 0.29)'"
as="'int((nf+2)/2) * W/nf * 0.29'" 
ps="'2*int((nf+2)/2) * (W/nf + 0.29)'"
nrd="'0.29 / W'" nrs="'0.29 / W'"
sa=0 sb=0 sd=0
model=pfet_g5v0d10v5
spiceprefix=X
}
C {devices/lab_pin.sym} -1500 -290 0 0 {name=p18 sig_type=std_logic lab=D17}
C {sky130_fd_pr/nfet_g5v0d10v5.sym} -940 10 0 0 {name=M1
L=12
W=2
nf=1
mult=192
ad="'int((nf+1)/2) * W/nf * 0.29'" 
pd="'2*int((nf+1)/2) * (W/nf + 0.29)'"
as="'int((nf+2)/2) * W/nf * 0.29'" 
ps="'2*int((nf+2)/2) * (W/nf + 0.29)'"
nrd="'0.29 / W'" nrs="'0.29 / W'"
sa=0 sb=0 sd=0
model=nfet_g5v0d10v5
spiceprefix=X
}
C {sky130_fd_pr/nfet_g5v0d10v5.sym} -1030 -170 0 0 {name=M2
L=10
W=60
nf=10
mult=20
ad="'int((nf+1)/2) * W/nf * 0.29'" 
pd="'2*int((nf+1)/2) * (W/nf + 0.29)'"
as="'int((nf+2)/2) * W/nf * 0.29'" 
ps="'2*int((nf+2)/2) * (W/nf + 0.29)'"
nrd="'0.29 / W'" nrs="'0.29 / W'"
sa=0 sb=0 sd=0
model=nfet_g5v0d10v5
spiceprefix=X
}
C {sky130_fd_pr/nfet_g5v0d10v5.sym} -820 -170 0 1 {name=M11
L=10
W=60
nf=10
mult=20
ad="'int((nf+1)/2) * W/nf * 0.29'" 
pd="'2*int((nf+1)/2) * (W/nf + 0.29)'"
as="'int((nf+2)/2) * W/nf * 0.29'" 
ps="'2*int((nf+2)/2) * (W/nf + 0.29)'"
nrd="'0.29 / W'" nrs="'0.29 / W'"
sa=0 sb=0 sd=0
model=nfet_g5v0d10v5
spiceprefix=X
}
C {sky130_fd_pr/pfet_g5v0d10v5.sym} 150 -520 0 0 {name=M20
L=16
W=2
nf=1
mult=388
ad="'int((nf+1)/2) * W/nf * 0.29'" 
pd="'2*int((nf+1)/2) * (W/nf + 0.29)'"
as="'int((nf+2)/2) * W/nf * 0.29'" 
ps="'2*int((nf+2)/2) * (W/nf + 0.29)'"
nrd="'0.29 / W'" nrs="'0.29 / W'"
sa=0 sb=0 sd=0
model=pfet_g5v0d10v5
spiceprefix=X
}
C {sky130_fd_pr/pfet_g5v0d10v5.sym} -110 -520 0 1 {name=M9
L=16
W=2
nf=1
mult=388
ad="'int((nf+1)/2) * W/nf * 0.29'" 
pd="'2*int((nf+1)/2) * (W/nf + 0.29)'"
as="'int((nf+2)/2) * W/nf * 0.29'" 
ps="'2*int((nf+2)/2) * (W/nf + 0.29)'"
nrd="'0.29 / W'" nrs="'0.29 / W'"
sa=0 sb=0 sd=0
model=pfet_g5v0d10v5
spiceprefix=X
}
C {sky130_fd_pr/pfet_g5v0d10v5.sym} 150 -380 0 0 {name=M7
L=20
W=1
nf=1
mult=16
ad="'int((nf+1)/2) * W/nf * 0.29'" 
pd="'2*int((nf+1)/2) * (W/nf + 0.29)'"
as="'int((nf+2)/2) * W/nf * 0.29'" 
ps="'2*int((nf+2)/2) * (W/nf + 0.29)'"
nrd="'0.29 / W'" nrs="'0.29 / W'"
sa=0 sb=0 sd=0
model=pfet_g5v0d10v5
spiceprefix=X
}
C {sky130_fd_pr/pfet_g5v0d10v5.sym} -110 -380 0 1 {name=M8
L=20
W=1
nf=1
mult=16
ad="'int((nf+1)/2) * W/nf * 0.29'" 
pd="'2*int((nf+1)/2) * (W/nf + 0.29)'"
as="'int((nf+2)/2) * W/nf * 0.29'" 
ps="'2*int((nf+2)/2) * (W/nf + 0.29)'"
nrd="'0.29 / W'" nrs="'0.29 / W'"
sa=0 sb=0 sd=0
model=pfet_g5v0d10v5
spiceprefix=X
}
C {sky130_fd_pr/nfet_g5v0d10v5.sym} 150 120 0 0 {name=M3
L=12
W=2
nf=1
mult=1
ad="'int((nf+1)/2) * W/nf * 0.29'" 
pd="'2*int((nf+1)/2) * (W/nf + 0.29)'"
as="'int((nf+2)/2) * W/nf * 0.29'" 
ps="'2*int((nf+2)/2) * (W/nf + 0.29)'"
nrd="'0.29 / W'" nrs="'0.29 / W'"
sa=0 sb=0 sd=0
model=nfet_g5v0d10v5
spiceprefix=X
}
C {sky130_fd_pr/nfet_g5v0d10v5.sym} -110 120 0 1 {name=M4
L=12
W=2
nf=1
mult=1
ad="'int((nf+1)/2) * W/nf * 0.29'" 
pd="'2*int((nf+1)/2) * (W/nf + 0.29)'"
as="'int((nf+2)/2) * W/nf * 0.29'" 
ps="'2*int((nf+2)/2) * (W/nf + 0.29)'"
nrd="'0.29 / W'" nrs="'0.29 / W'"
sa=0 sb=0 sd=0
model=nfet_g5v0d10v5
spiceprefix=X
}
C {sky130_fd_pr/nfet_g5v0d10v5.sym} -110 -90 0 1 {name=M5
L=20
W=4
nf=1
mult=2
ad="'int((nf+1)/2) * W/nf * 0.29'" 
pd="'2*int((nf+1)/2) * (W/nf + 0.29)'"
as="'int((nf+2)/2) * W/nf * 0.29'" 
ps="'2*int((nf+2)/2) * (W/nf + 0.29)'"
nrd="'0.29 / W'" nrs="'0.29 / W'"
sa=0 sb=0 sd=0
model=nfet_g5v0d10v5
spiceprefix=X
}
C {sky130_fd_pr/nfet_g5v0d10v5.sym} 150 -90 0 0 {name=M6
L=20
W=4
nf=1
mult=2
ad="'int((nf+1)/2) * W/nf * 0.29'" 
pd="'2*int((nf+1)/2) * (W/nf + 0.29)'"
as="'int((nf+2)/2) * W/nf * 0.29'" 
ps="'2*int((nf+2)/2) * (W/nf + 0.29)'"
nrd="'0.29 / W'" nrs="'0.29 / W'"
sa=0 sb=0 sd=0
model=nfet_g5v0d10v5
spiceprefix=X
}
C {devices/lab_pin.sym} -840 -90 0 0 {name=p20 sig_type=std_logic lab=P}
C {sky130_fd_pr/nfet_g5v0d10v5.sym} -1480 -110 0 1 {name=M10
L=20
W=4
nf=1
mult=4
ad="'int((nf+1)/2) * W/nf * 0.29'" 
pd="'2*int((nf+1)/2) * (W/nf + 0.29)'"
as="'int((nf+2)/2) * W/nf * 0.29'" 
ps="'2*int((nf+2)/2) * (W/nf + 0.29)'"
nrd="'0.29 / W'" nrs="'0.29 / W'"
sa=0 sb=0 sd=0
model=nfet_g5v0d10v5
spiceprefix=X
}
C {devices/lab_pin.sym} -1500 -10 0 1 {name=p11 sig_type=std_logic lab=D13}
C {devices/lab_pin.sym} -320 -450 1 0 {name=p19 sig_type=std_logic lab=A}
C {sky130_fd_pr/pfet_g5v0d10v5.sym} 1130 -480 0 0 {name=M19
L=16
W=2
nf=1
mult=4
ad="'int((nf+1)/2) * W/nf * 0.29'" 
pd="'2*int((nf+1)/2) * (W/nf + 0.29)'"
as="'int((nf+2)/2) * W/nf * 0.29'" 
ps="'2*int((nf+2)/2) * (W/nf + 0.29)'"
nrd="'0.29 / W'" nrs="'0.29 / W'"
sa=0 sb=0 sd=0
model=pfet_g5v0d10v5
spiceprefix=X
}
C {sky130_fd_pr/pfet_g5v0d10v5.sym} 870 -480 0 1 {name=M21
L=16
W=2
nf=1
mult=4
ad="'int((nf+1)/2) * W/nf * 0.29'" 
pd="'2*int((nf+1)/2) * (W/nf + 0.29)'"
as="'int((nf+2)/2) * W/nf * 0.29'" 
ps="'2*int((nf+2)/2) * (W/nf + 0.29)'"
nrd="'0.29 / W'" nrs="'0.29 / W'"
sa=0 sb=0 sd=0
model=pfet_g5v0d10v5
spiceprefix=X
}
C {sky130_fd_pr/nfet_g5v0d10v5.sym} 1020 -240 0 1 {name=M22
L=12
W=4
nf=2
mult=2
ad="'int((nf+1)/2) * W/nf * 0.29'" 
pd="'2*int((nf+1)/2) * (W/nf + 0.29)'"
as="'int((nf+2)/2) * W/nf * 0.29'" 
ps="'2*int((nf+2)/2) * (W/nf + 0.29)'"
nrd="'0.29 / W'" nrs="'0.29 / W'"
sa=0 sb=0 sd=0
model=nfet_g5v0d10v5
spiceprefix=X
}
C {sky130_fd_pr/nfet_g5v0d10v5.sym} 1480 -240 0 1 {name=M24
L=12
W=4
nf=2
mult=2
ad="'int((nf+1)/2) * W/nf * 0.29'" 
pd="'2*int((nf+1)/2) * (W/nf + 0.29)'"
as="'int((nf+2)/2) * W/nf * 0.29'" 
ps="'2*int((nf+2)/2) * (W/nf + 0.29)'"
nrd="'0.29 / W'" nrs="'0.29 / W'"
sa=0 sb=0 sd=0
model=nfet_g5v0d10v5
spiceprefix=X
}
C {sky130_fd_pr/nfet_g5v0d10v5.sym} 830 -240 0 0 {name=M25
L=12
W=4
nf=2
mult=2
ad="'int((nf+1)/2) * W/nf * 0.29'" 
pd="'2*int((nf+1)/2) * (W/nf + 0.29)'"
as="'int((nf+2)/2) * W/nf * 0.29'" 
ps="'2*int((nf+2)/2) * (W/nf + 0.29)'"
nrd="'0.29 / W'" nrs="'0.29 / W'"
sa=0 sb=0 sd=0
model=nfet_g5v0d10v5
spiceprefix=X
}
C {devices/lab_pin.sym} 1170 50 0 0 {name=p27 sig_type=std_logic lab=VB4}
C {sky130_fd_pr/nfet_g5v0d10v5.sym} 1280 50 0 0 {name=M26
L=12
W=2
nf=1
mult=1
ad="'int((nf+1)/2) * W/nf * 0.29'" 
pd="'2*int((nf+1)/2) * (W/nf + 0.29)'"
as="'int((nf+2)/2) * W/nf * 0.29'" 
ps="'2*int((nf+2)/2) * (W/nf + 0.29)'"
nrd="'0.29 / W'" nrs="'0.29 / W'"
sa=0 sb=0 sd=0
model=nfet_g5v0d10v5
spiceprefix=X
}
C {sky130_fd_pr/nfet_g5v0d10v5.sym} 1020 50 0 1 {name=M27
L=12
W=2
nf=1
mult=1
ad="'int((nf+1)/2) * W/nf * 0.29'" 
pd="'2*int((nf+1)/2) * (W/nf + 0.29)'"
as="'int((nf+2)/2) * W/nf * 0.29'" 
ps="'2*int((nf+2)/2) * (W/nf + 0.29)'"
nrd="'0.29 / W'" nrs="'0.29 / W'"
sa=0 sb=0 sd=0
model=nfet_g5v0d10v5
spiceprefix=X
}
C {devices/lab_pin.sym} -130 -240 0 0 {name=p28 sig_type=std_logic lab=VON}
C {devices/lab_pin.sym} 170 -240 2 0 {name=p29 sig_type=std_logic lab=VOP}
C {devices/lab_pin.sym} 930 -240 1 0 {name=p30 sig_type=std_logic lab=0}
C {devices/lab_pin.sym} 770 -240 0 0 {name=p31 sig_type=std_logic lab=VON}
C {devices/lab_pin.sym} 1550 -240 0 1 {name=p32 sig_type=std_logic lab=VOP}
C {devices/lab_pin.sym} 1390 -240 1 0 {name=p33 sig_type=std_logic lab=0}
C {devices/lab_pin.sym} 1190 -240 1 0 {name=p12 sig_type=std_logic lab=VCM}
C {devices/lab_pin.sym} 1190 120 1 0 {name=p25 sig_type=std_logic lab=0}
C {devices/vsource.sym} -975 -880 0 0 {name=V1 value=2.5 savecurrent=false}
C {devices/lab_pin.sym} -975 -950 0 0 {name=p34 sig_type=std_logic lab=VCM}
C {devices/lab_pin.sym} 1050 -550 1 0 {name=p35 sig_type=std_logic lab=VDD}
C {devices/vsource.sym} -790 -880 0 0 {name=V3 value="dc 2.5 ac 1u 180"  net_name=true}
C {devices/lab_pin.sym} -790 -940 0 0 {name=p23 sig_type=std_logic lab=INN}
C {devices/lab_pin.sym} 1060 -460 0 0 {name=p21 sig_type=std_logic lab=VB1}
C {sky130_fd_pr/nfet_g5v0d10v5.sym} 1280 -240 0 0 {name=M23
L=12
W=4
nf=2
mult=2
ad="'int((nf+1)/2) * W/nf * 0.29'" 
pd="'2*int((nf+1)/2) * (W/nf + 0.29)'"
as="'int((nf+2)/2) * W/nf * 0.29'" 
ps="'2*int((nf+2)/2) * (W/nf + 0.29)'"
nrd="'0.29 / W'" nrs="'0.29 / W'"
sa=0 sb=0 sd=0
model=nfet_g5v0d10v5
spiceprefix=X
}
C {devices/lab_pin.sym} -1610 -350 1 0 {name=p36 sig_type=std_logic lab=VB}
C {sky130_fd_pr/nfet_g5v0d10v5.sym} 300 -230 0 0 {name=M28
L=1
W=50
nf=1
mult=10
ad="'int((nf+1)/2) * W/nf * 0.29'" 
pd="'2*int((nf+1)/2) * (W/nf + 0.29)'"
as="'int((nf+2)/2) * W/nf * 0.29'" 
ps="'2*int((nf+2)/2) * (W/nf + 0.29)'"
nrd="'0.29 / W'" nrs="'0.29 / W'"
sa=0 sb=0 sd=0
model=nfet_g5v0d10v5
spiceprefix=X
}
C {sky130_fd_pr/res_generic_l1.sym} 320 -110 0 0 {name=R1
W=1
L=100000000
model=res_generic_l1
mult=1}
C {sky130_fd_pr/nfet_g5v0d10v5.sym} -250 -220 0 1 {name=M29
L=1
W=50
nf=1
mult=10
ad="'int((nf+1)/2) * W/nf * 0.29'" 
pd="'2*int((nf+1)/2) * (W/nf + 0.29)'"
as="'int((nf+2)/2) * W/nf * 0.29'" 
ps="'2*int((nf+2)/2) * (W/nf + 0.29)'"
nrd="'0.29 / W'" nrs="'0.29 / W'"
sa=0 sb=0 sd=0
model=nfet_g5v0d10v5
spiceprefix=X
}
C {sky130_fd_pr/res_generic_l1.sym} -270 -70 0 0 {name=R2
W=1
L=100000000
model=res_generic_l1
mult=1}
C {devices/lab_pin.sym} -270 -320 0 0 {name=p37 sig_type=std_logic lab=VDD}
C {sky130_fd_pr/cap_mim_m3_1.sym} -360 -70 0 0 {name=C1 model=cap_mim_m3_1 W=10000 L=1.3 MF=1 spiceprefix=X}
C {sky130_fd_pr/res_generic_l1.sym} -480 -70 0 0 {name=R3
W=1.4
L=500
model=res_generic_l1
mult=1}
C {sky130_fd_pr/cap_mim_m3_1.sym} 550 -70 0 0 {name=C2 model=cap_mim_m3_1 W=10000 L=1.3 MF=1 spiceprefix=X}
C {sky130_fd_pr/res_generic_l1.sym} 430 -70 0 0 {name=R4
W=1.34
L=500
model=res_generic_l1
mult=1}
C {devices/lab_pin.sym} 510 -160 1 0 {name=p38 sig_type=std_logic lab=VP}
C {devices/lab_pin.sym} -400 -140 1 0 {name=p39 sig_type=std_logic lab=VN}
C {devices/lab_pin.sym} -130 0 0 0 {name=p41 sig_type=std_logic lab=P1}
C {devices/lab_pin.sym} 170 0 0 0 {name=p42 sig_type=std_logic lab=P2}
C {devices/lab_pin.sym} -1230 -170 0 0 {name=p43 sig_type=std_logic lab=INN}
C {devices/lab_pin.sym} -710 240 1 0 {name=p5 sig_type=std_logic lab=0}
C {devices/lab_pin.sym} -620 -170 2 0 {name=p6 sig_type=std_logic lab=INP}
C {devices/vsource.sym} -1170 -880 0 0 {name=V2 value="dc 2.5 ac 1u 0"  net_name=true}
C {devices/lab_pin.sym} -1170 -940 0 0 {name=p24 sig_type=std_logic lab=INP}
C {devices/isource.sym} -1900 -2110 0 0 {name=I1 value=10u
}
C {devices/lab_pin.sym} -1760 -1930 0 0 {name=p40 sig_type=std_logic lab=VB4
}
C {devices/lab_pin.sym} -930 -2030 0 0 {name=p44 sig_type=std_logic lab=VB4}
C {devices/lab_pin.sym} 110 -1920 0 0 {name=p45 sig_type=std_logic lab=VB4}
C {devices/lab_pin.sym} -840 -2210 0 0 {name=p46 sig_type=std_logic lab=0}
C {devices/lab_pin.sym} -380 -1800 1 0 {name=p47 sig_type=std_logic lab=0}
C {devices/lab_pin.sym} -1770 -1810 1 0 {name=p48 sig_type=std_logic lab=0}
C {devices/lab_pin.sym} -1770 -2480 1 0 {name=p49 sig_type=std_logic lab=VDD}
C {devices/lab_pin.sym} 50 -2650 1 0 {name=p50 sig_type=std_logic lab=VDD}
C {devices/lab_pin.sym} 100 -2560 1 0 {name=p51 sig_type=std_logic lab=VB1}
C {devices/lab_pin.sym} -1500 -2270 1 0 {name=p52 sig_type=std_logic lab=VB2}
C {devices/lab_pin.sym} 110 -2420 3 0 {name=p53 sig_type=std_logic lab=VB2}
C {devices/lab_pin.sym} -1330 -2190 2 0 {name=p54 sig_type=std_logic lab=VB3}
C {devices/lab_pin.sym} 110 -2130 1 0 {name=p55 sig_type=std_logic lab=VB3}
C {sky130_fd_pr/nfet_g5v0d10v5.sym} -1400 -1960 0 1 {name=M30
L=5
W=8
nf=1
mult=2
ad="'int((nf+1)/2) * W/nf * 0.29'" 
pd="'2*int((nf+1)/2) * (W/nf + 0.29)'"
as="'int((nf+2)/2) * W/nf * 0.29'" 
ps="'2*int((nf+2)/2) * (W/nf + 0.29)'"
nrd="'0.29 / W'" nrs="'0.29 / W'"
sa=0 sb=0 sd=0
model=nfet_g5v0d10v5
spiceprefix=X
}
C {sky130_fd_pr/nfet_g5v0d10v5.sym} -1670 -1930 0 0 {name=M31
L=12
W=2
nf=1
mult=2
ad="'int((nf+1)/2) * W/nf * 0.29'" 
pd="'2*int((nf+1)/2) * (W/nf + 0.29)'"
as="'int((nf+2)/2) * W/nf * 0.29'" 
ps="'2*int((nf+2)/2) * (W/nf + 0.29)'"
nrd="'0.29 / W'" nrs="'0.29 / W'"
sa=0 sb=0 sd=0
model=nfet_g5v0d10v5
spiceprefix=X
}
C {sky130_fd_pr/nfet_g5v0d10v5.sym} -1880 -1930 0 1 {name=M32
L=12
W=2
nf=1
mult=2
ad="'int((nf+1)/2) * W/nf * 0.29'" 
pd="'2*int((nf+1)/2) * (W/nf + 0.29)'"
as="'int((nf+2)/2) * W/nf * 0.29'" 
ps="'2*int((nf+2)/2) * (W/nf + 0.29)'"
nrd="'0.29 / W'" nrs="'0.29 / W'"
sa=0 sb=0 sd=0
model=nfet_g5v0d10v5
spiceprefix=X
}
C {sky130_fd_pr/pfet_g5v0d10v5.sym} -1630 -2270 0 1 {name=M33
L=20
W=1
nf=1
mult=32
ad="'int((nf+1)/2) * W/nf * 0.29'" 
pd="'2*int((nf+1)/2) * (W/nf + 0.29)'"
as="'int((nf+2)/2) * W/nf * 0.29'" 
ps="'2*int((nf+2)/2) * (W/nf + 0.29)'"
nrd="'0.29 / W'" nrs="'0.29 / W'"
sa=0 sb=0 sd=0
model=pfet_g5v0d10v5
spiceprefix=X
}
C {sky130_fd_pr/pfet_g5v0d10v5.sym} -1630 -2390 0 1 {name=M34
L=2
W=10
nf=1
mult=2
ad="'int((nf+1)/2) * W/nf * 0.29'" 
pd="'2*int((nf+1)/2) * (W/nf + 0.29)'"
as="'int((nf+2)/2) * W/nf * 0.29'" 
ps="'2*int((nf+2)/2) * (W/nf + 0.29)'"
nrd="'0.29 / W'" nrs="'0.29 / W'"
sa=0 sb=0 sd=0
model=pfet_g5v0d10v5
spiceprefix=X
}
C {sky130_fd_pr/pfet_g5v0d10v5.sym} -1440 -2390 0 0 {name=M35
L=2
W=10
nf=1
mult=2
ad="'int((nf+1)/2) * W/nf * 0.29'" 
pd="'2*int((nf+1)/2) * (W/nf + 0.29)'"
as="'int((nf+2)/2) * W/nf * 0.29'" 
ps="'2*int((nf+2)/2) * (W/nf + 0.29)'"
nrd="'0.29 / W'" nrs="'0.29 / W'"
sa=0 sb=0 sd=0
model=pfet_g5v0d10v5
spiceprefix=X
}
C {sky130_fd_pr/pfet_g5v0d10v5.sym} -1440 -2270 0 0 {name=M36
L=20
W=1
nf=1
mult=32
ad="'int((nf+1)/2) * W/nf * 0.29'" 
pd="'2*int((nf+1)/2) * (W/nf + 0.29)'"
as="'int((nf+2)/2) * W/nf * 0.29'" 
ps="'2*int((nf+2)/2) * (W/nf + 0.29)'"
nrd="'0.29 / W'" nrs="'0.29 / W'"
sa=0 sb=0 sd=0
model=pfet_g5v0d10v5
spiceprefix=X
}
C {devices/lab_pin.sym} -1420 -2330 0 0 {name=p56 sig_type=std_logic lab=D17}
C {sky130_fd_pr/nfet_g5v0d10v5.sym} -860 -2030 0 0 {name=M37
L=12
W=2
nf=1
mult=192
ad="'int((nf+1)/2) * W/nf * 0.29'" 
pd="'2*int((nf+1)/2) * (W/nf + 0.29)'"
as="'int((nf+2)/2) * W/nf * 0.29'" 
ps="'2*int((nf+2)/2) * (W/nf + 0.29)'"
nrd="'0.29 / W'" nrs="'0.29 / W'"
sa=0 sb=0 sd=0
model=nfet_g5v0d10v5
spiceprefix=X
}
C {sky130_fd_pr/nfet_g5v0d10v5.sym} -950 -2210 0 0 {name=M38
L=10
W=60
nf=10
mult=20
ad="'int((nf+1)/2) * W/nf * 0.29'" 
pd="'2*int((nf+1)/2) * (W/nf + 0.29)'"
as="'int((nf+2)/2) * W/nf * 0.29'" 
ps="'2*int((nf+2)/2) * (W/nf + 0.29)'"
nrd="'0.29 / W'" nrs="'0.29 / W'"
sa=0 sb=0 sd=0
model=nfet_g5v0d10v5
spiceprefix=X
}
C {sky130_fd_pr/nfet_g5v0d10v5.sym} -740 -2210 0 1 {name=M39
L=10
W=60
nf=10
mult=20
ad="'int((nf+1)/2) * W/nf * 0.29'" 
pd="'2*int((nf+1)/2) * (W/nf + 0.29)'"
as="'int((nf+2)/2) * W/nf * 0.29'" 
ps="'2*int((nf+2)/2) * (W/nf + 0.29)'"
nrd="'0.29 / W'" nrs="'0.29 / W'"
sa=0 sb=0 sd=0
model=nfet_g5v0d10v5
spiceprefix=X
}
C {sky130_fd_pr/pfet_g5v0d10v5.sym} 230 -2560 0 0 {name=M40
L=16
W=2
nf=1
mult=388
ad="'int((nf+1)/2) * W/nf * 0.29'" 
pd="'2*int((nf+1)/2) * (W/nf + 0.29)'"
as="'int((nf+2)/2) * W/nf * 0.29'" 
ps="'2*int((nf+2)/2) * (W/nf + 0.29)'"
nrd="'0.29 / W'" nrs="'0.29 / W'"
sa=0 sb=0 sd=0
model=pfet_g5v0d10v5
spiceprefix=X
}
C {sky130_fd_pr/pfet_g5v0d10v5.sym} -30 -2560 0 1 {name=M41
L=16
W=2
nf=1
mult=388
ad="'int((nf+1)/2) * W/nf * 0.29'" 
pd="'2*int((nf+1)/2) * (W/nf + 0.29)'"
as="'int((nf+2)/2) * W/nf * 0.29'" 
ps="'2*int((nf+2)/2) * (W/nf + 0.29)'"
nrd="'0.29 / W'" nrs="'0.29 / W'"
sa=0 sb=0 sd=0
model=pfet_g5v0d10v5
spiceprefix=X
}
C {sky130_fd_pr/pfet_g5v0d10v5.sym} 230 -2420 0 0 {name=M42
L=20
W=1
nf=1
mult=16
ad="'int((nf+1)/2) * W/nf * 0.29'" 
pd="'2*int((nf+1)/2) * (W/nf + 0.29)'"
as="'int((nf+2)/2) * W/nf * 0.29'" 
ps="'2*int((nf+2)/2) * (W/nf + 0.29)'"
nrd="'0.29 / W'" nrs="'0.29 / W'"
sa=0 sb=0 sd=0
model=pfet_g5v0d10v5
spiceprefix=X
}
C {sky130_fd_pr/pfet_g5v0d10v5.sym} -30 -2420 0 1 {name=M43
L=20
W=1
nf=1
mult=16
ad="'int((nf+1)/2) * W/nf * 0.29'" 
pd="'2*int((nf+1)/2) * (W/nf + 0.29)'"
as="'int((nf+2)/2) * W/nf * 0.29'" 
ps="'2*int((nf+2)/2) * (W/nf + 0.29)'"
nrd="'0.29 / W'" nrs="'0.29 / W'"
sa=0 sb=0 sd=0
model=pfet_g5v0d10v5
spiceprefix=X
}
C {sky130_fd_pr/nfet_g5v0d10v5.sym} 230 -1920 0 0 {name=M44
L=12
W=2
nf=1
mult=1
ad="'int((nf+1)/2) * W/nf * 0.29'" 
pd="'2*int((nf+1)/2) * (W/nf + 0.29)'"
as="'int((nf+2)/2) * W/nf * 0.29'" 
ps="'2*int((nf+2)/2) * (W/nf + 0.29)'"
nrd="'0.29 / W'" nrs="'0.29 / W'"
sa=0 sb=0 sd=0
model=nfet_g5v0d10v5
spiceprefix=X
}
C {sky130_fd_pr/nfet_g5v0d10v5.sym} -30 -1920 0 1 {name=M45
L=12
W=2
nf=1
mult=1
ad="'int((nf+1)/2) * W/nf * 0.29'" 
pd="'2*int((nf+1)/2) * (W/nf + 0.29)'"
as="'int((nf+2)/2) * W/nf * 0.29'" 
ps="'2*int((nf+2)/2) * (W/nf + 0.29)'"
nrd="'0.29 / W'" nrs="'0.29 / W'"
sa=0 sb=0 sd=0
model=nfet_g5v0d10v5
spiceprefix=X
}
C {sky130_fd_pr/nfet_g5v0d10v5.sym} -30 -2130 0 1 {name=M46
L=20
W=4
nf=1
mult=2
ad="'int((nf+1)/2) * W/nf * 0.29'" 
pd="'2*int((nf+1)/2) * (W/nf + 0.29)'"
as="'int((nf+2)/2) * W/nf * 0.29'" 
ps="'2*int((nf+2)/2) * (W/nf + 0.29)'"
nrd="'0.29 / W'" nrs="'0.29 / W'"
sa=0 sb=0 sd=0
model=nfet_g5v0d10v5
spiceprefix=X
}
C {sky130_fd_pr/nfet_g5v0d10v5.sym} 230 -2130 0 0 {name=M47
L=20
W=4
nf=1
mult=2
ad="'int((nf+1)/2) * W/nf * 0.29'" 
pd="'2*int((nf+1)/2) * (W/nf + 0.29)'"
as="'int((nf+2)/2) * W/nf * 0.29'" 
ps="'2*int((nf+2)/2) * (W/nf + 0.29)'"
nrd="'0.29 / W'" nrs="'0.29 / W'"
sa=0 sb=0 sd=0
model=nfet_g5v0d10v5
spiceprefix=X
}
C {devices/lab_pin.sym} -760 -2130 0 0 {name=p57 sig_type=std_logic lab=P}
C {sky130_fd_pr/nfet_g5v0d10v5.sym} -1400 -2150 0 1 {name=M48
L=20
W=4
nf=1
mult=4
ad="'int((nf+1)/2) * W/nf * 0.29'" 
pd="'2*int((nf+1)/2) * (W/nf + 0.29)'"
as="'int((nf+2)/2) * W/nf * 0.29'" 
ps="'2*int((nf+2)/2) * (W/nf + 0.29)'"
nrd="'0.29 / W'" nrs="'0.29 / W'"
sa=0 sb=0 sd=0
model=nfet_g5v0d10v5
spiceprefix=X
}
C {devices/lab_pin.sym} -1420 -2050 0 1 {name=p58 sig_type=std_logic lab=D13}
C {devices/lab_pin.sym} -240 -2490 1 0 {name=p59 sig_type=std_logic lab=A}
C {sky130_fd_pr/pfet_g5v0d10v5.sym} 1210 -2520 0 0 {name=M49
L=16
W=2
nf=1
mult=4
ad="'int((nf+1)/2) * W/nf * 0.29'" 
pd="'2*int((nf+1)/2) * (W/nf + 0.29)'"
as="'int((nf+2)/2) * W/nf * 0.29'" 
ps="'2*int((nf+2)/2) * (W/nf + 0.29)'"
nrd="'0.29 / W'" nrs="'0.29 / W'"
sa=0 sb=0 sd=0
model=pfet_g5v0d10v5
spiceprefix=X
}
C {sky130_fd_pr/pfet_g5v0d10v5.sym} 950 -2520 0 1 {name=M50
L=16
W=2
nf=1
mult=4
ad="'int((nf+1)/2) * W/nf * 0.29'" 
pd="'2*int((nf+1)/2) * (W/nf + 0.29)'"
as="'int((nf+2)/2) * W/nf * 0.29'" 
ps="'2*int((nf+2)/2) * (W/nf + 0.29)'"
nrd="'0.29 / W'" nrs="'0.29 / W'"
sa=0 sb=0 sd=0
model=pfet_g5v0d10v5
spiceprefix=X
}
C {sky130_fd_pr/nfet_g5v0d10v5.sym} 1100 -2280 0 1 {name=M51
L=12
W=4
nf=2
mult=2
ad="'int((nf+1)/2) * W/nf * 0.29'" 
pd="'2*int((nf+1)/2) * (W/nf + 0.29)'"
as="'int((nf+2)/2) * W/nf * 0.29'" 
ps="'2*int((nf+2)/2) * (W/nf + 0.29)'"
nrd="'0.29 / W'" nrs="'0.29 / W'"
sa=0 sb=0 sd=0
model=nfet_g5v0d10v5
spiceprefix=X
}
C {sky130_fd_pr/nfet_g5v0d10v5.sym} 1560 -2280 0 1 {name=M52
L=12
W=4
nf=2
mult=2
ad="'int((nf+1)/2) * W/nf * 0.29'" 
pd="'2*int((nf+1)/2) * (W/nf + 0.29)'"
as="'int((nf+2)/2) * W/nf * 0.29'" 
ps="'2*int((nf+2)/2) * (W/nf + 0.29)'"
nrd="'0.29 / W'" nrs="'0.29 / W'"
sa=0 sb=0 sd=0
model=nfet_g5v0d10v5
spiceprefix=X
}
C {sky130_fd_pr/nfet_g5v0d10v5.sym} 910 -2280 0 0 {name=M53
L=12
W=4
nf=2
mult=2
ad="'int((nf+1)/2) * W/nf * 0.29'" 
pd="'2*int((nf+1)/2) * (W/nf + 0.29)'"
as="'int((nf+2)/2) * W/nf * 0.29'" 
ps="'2*int((nf+2)/2) * (W/nf + 0.29)'"
nrd="'0.29 / W'" nrs="'0.29 / W'"
sa=0 sb=0 sd=0
model=nfet_g5v0d10v5
spiceprefix=X
}
C {devices/lab_pin.sym} 1250 -1990 0 0 {name=p60 sig_type=std_logic lab=VB4}
C {sky130_fd_pr/nfet_g5v0d10v5.sym} 1360 -1990 0 0 {name=M54
L=12
W=2
nf=1
mult=1
ad="'int((nf+1)/2) * W/nf * 0.29'" 
pd="'2*int((nf+1)/2) * (W/nf + 0.29)'"
as="'int((nf+2)/2) * W/nf * 0.29'" 
ps="'2*int((nf+2)/2) * (W/nf + 0.29)'"
nrd="'0.29 / W'" nrs="'0.29 / W'"
sa=0 sb=0 sd=0
model=nfet_g5v0d10v5
spiceprefix=X
}
C {sky130_fd_pr/nfet_g5v0d10v5.sym} 1100 -1990 0 1 {name=M55
L=12
W=2
nf=1
mult=1
ad="'int((nf+1)/2) * W/nf * 0.29'" 
pd="'2*int((nf+1)/2) * (W/nf + 0.29)'"
as="'int((nf+2)/2) * W/nf * 0.29'" 
ps="'2*int((nf+2)/2) * (W/nf + 0.29)'"
nrd="'0.29 / W'" nrs="'0.29 / W'"
sa=0 sb=0 sd=0
model=nfet_g5v0d10v5
spiceprefix=X
}
C {devices/lab_pin.sym} -50 -2280 0 0 {name=p61 sig_type=std_logic lab=VON}
C {devices/lab_pin.sym} 250 -2280 2 0 {name=p62 sig_type=std_logic lab=VOP}
C {devices/lab_pin.sym} 1010 -2280 1 0 {name=p63 sig_type=std_logic lab=0}
C {devices/lab_pin.sym} 850 -2280 0 0 {name=p64 sig_type=std_logic lab=VON}
C {devices/lab_pin.sym} 1630 -2280 0 1 {name=p65 sig_type=std_logic lab=VOP}
C {devices/lab_pin.sym} 1470 -2280 1 0 {name=p66 sig_type=std_logic lab=0}
C {devices/lab_pin.sym} 1270 -2280 1 0 {name=p67 sig_type=std_logic lab=VCM}
C {devices/lab_pin.sym} 1270 -1920 1 0 {name=p68 sig_type=std_logic lab=0}
C {devices/lab_pin.sym} 1130 -2590 1 0 {name=p69 sig_type=std_logic lab=VDD}
C {devices/lab_pin.sym} 1140 -2500 0 0 {name=p70 sig_type=std_logic lab=VB1}
C {sky130_fd_pr/nfet_g5v0d10v5.sym} 1360 -2280 0 0 {name=M56
L=12
W=4
nf=2
mult=2
ad="'int((nf+1)/2) * W/nf * 0.29'" 
pd="'2*int((nf+1)/2) * (W/nf + 0.29)'"
as="'int((nf+2)/2) * W/nf * 0.29'" 
ps="'2*int((nf+2)/2) * (W/nf + 0.29)'"
nrd="'0.29 / W'" nrs="'0.29 / W'"
sa=0 sb=0 sd=0
model=nfet_g5v0d10v5
spiceprefix=X
}
C {devices/lab_pin.sym} -1530 -2390 1 0 {name=p71 sig_type=std_logic lab=VB}
C {sky130_fd_pr/nfet_g5v0d10v5.sym} 380 -2270 0 0 {name=M57
L=1
W=50
nf=1
mult=10
ad="'int((nf+1)/2) * W/nf * 0.29'" 
pd="'2*int((nf+1)/2) * (W/nf + 0.29)'"
as="'int((nf+2)/2) * W/nf * 0.29'" 
ps="'2*int((nf+2)/2) * (W/nf + 0.29)'"
nrd="'0.29 / W'" nrs="'0.29 / W'"
sa=0 sb=0 sd=0
model=nfet_g5v0d10v5
spiceprefix=X
}
C {sky130_fd_pr/res_generic_l1.sym} 400 -2150 0 0 {name=R5
W=1
L=100000000
model=res_generic_l1
mult=1}
C {sky130_fd_pr/nfet_g5v0d10v5.sym} -170 -2260 0 1 {name=M58
L=1
W=50
nf=1
mult=10
ad="'int((nf+1)/2) * W/nf * 0.29'" 
pd="'2*int((nf+1)/2) * (W/nf + 0.29)'"
as="'int((nf+2)/2) * W/nf * 0.29'" 
ps="'2*int((nf+2)/2) * (W/nf + 0.29)'"
nrd="'0.29 / W'" nrs="'0.29 / W'"
sa=0 sb=0 sd=0
model=nfet_g5v0d10v5
spiceprefix=X
}
C {sky130_fd_pr/res_generic_l1.sym} -190 -2110 0 0 {name=R6
W=1
L=100000000
model=res_generic_l1
mult=1}
C {devices/lab_pin.sym} -190 -2360 0 0 {name=p72 sig_type=std_logic lab=VDD}
C {sky130_fd_pr/cap_mim_m3_1.sym} -280 -2110 0 0 {name=C3 model=cap_mim_m3_1 W=10000 L=1.3 MF=1 spiceprefix=X}
C {sky130_fd_pr/res_generic_l1.sym} -400 -2110 0 0 {name=R7
W=1.4
L=500
model=res_generic_l1
mult=1}
C {sky130_fd_pr/cap_mim_m3_1.sym} 630 -2110 0 0 {name=C4 model=cap_mim_m3_1 W=10000 L=1.3 MF=1 spiceprefix=X}
C {sky130_fd_pr/res_generic_l1.sym} 510 -2110 0 0 {name=R8
W=1.34
L=500
model=res_generic_l1
mult=1}
C {devices/lab_pin.sym} 590 -2200 1 0 {name=p73 sig_type=std_logic lab=VP}
C {devices/lab_pin.sym} -320 -2180 1 0 {name=p74 sig_type=std_logic lab=VN}
C {devices/lab_pin.sym} -50 -2040 0 0 {name=p75 sig_type=std_logic lab=P1}
C {devices/lab_pin.sym} 250 -2040 0 0 {name=p76 sig_type=std_logic lab=P2}
C {devices/lab_pin.sym} -1150 -2210 0 0 {name=p77 sig_type=std_logic lab=INN}
C {devices/lab_pin.sym} -630 -1800 1 0 {name=p78 sig_type=std_logic lab=0}
